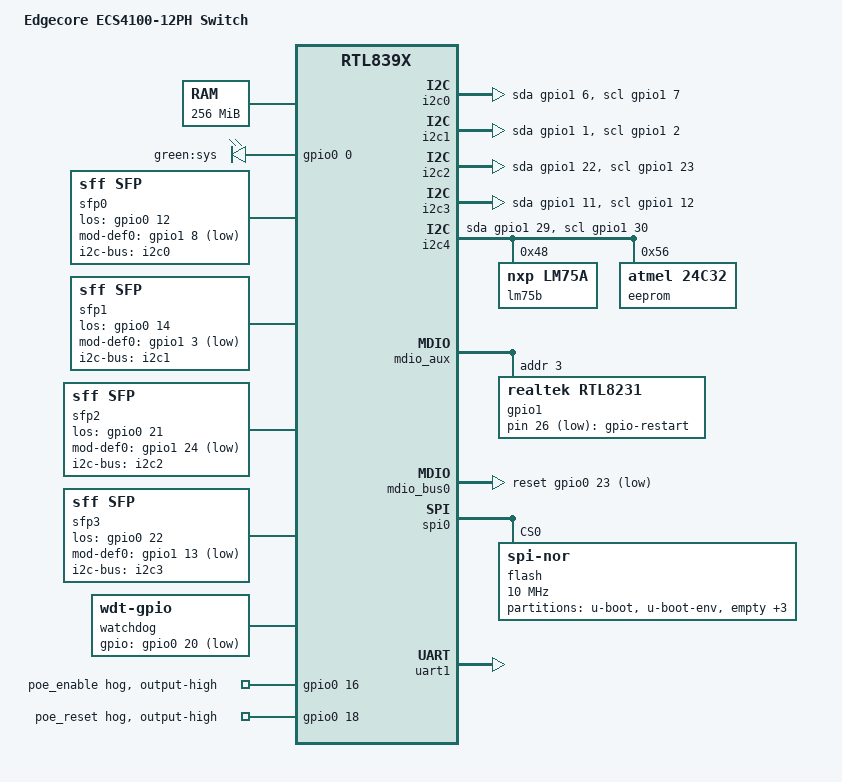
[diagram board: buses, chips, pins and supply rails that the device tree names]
// SPDX-License-Identifier: GPL-2.0-or-later

#include "rtl839x.dtsi"

#include <dt-bindings/input/input.h>
#include <dt-bindings/gpio/gpio.h>

/ {
	compatible = "edgecore,ecs4100-12ph", "realtek,rtl839x-soc";
	model = "Edgecore ECS4100-12PH Switch";

	aliases {
		label-mac-device = &ethernet0;
		led-boot = &led_sys;
		led-failsafe = &led_sys;
		led-running = &led_sys;
		led-upgrade = &led_sys;
	};

	memory@0 {
		device_type = "memory";
		reg = <0x0 0x10000000>;
	};

	leds {
		pinctrl-names = "default";
		pinctrl-0 = <&pinmux_disable_sys_led>;
		compatible = "gpio-leds";

		led_sys: sys {
			label = "green:sys";
			gpios = <&gpio0 0 GPIO_ACTIVE_HIGH>;
		};
	};

	gpio-restart {
		compatible = "gpio-restart";
		gpios = <&gpio1 26 GPIO_ACTIVE_LOW>;
	};

	i2c0: i2c-gpio-0 {
		compatible = "i2c-gpio";
		sda-gpios = <&gpio1 6 (GPIO_ACTIVE_HIGH | GPIO_OPEN_DRAIN)>;
		scl-gpios = <&gpio1 7 (GPIO_ACTIVE_HIGH | GPIO_OPEN_DRAIN)>;
		i2c-gpio,delay-us = <2>;
		#address-cells = <1>;
		#size-cells = <0>;
	};

	sfp0: sfp-p9 {
		compatible = "sff,sfp";
		i2c-bus = <&i2c0>;
		los-gpio = <&gpio0 12 GPIO_ACTIVE_HIGH>;
		mod-def0-gpio = <&gpio1 8 GPIO_ACTIVE_LOW>;
	};

	i2c1: i2c-gpio-1 {
		compatible = "i2c-gpio";
		sda-gpios = <&gpio1 1 (GPIO_ACTIVE_HIGH | GPIO_OPEN_DRAIN)>;
		scl-gpios = <&gpio1 2 (GPIO_ACTIVE_HIGH | GPIO_OPEN_DRAIN)>;
		i2c-gpio,delay-us = <2>;
		#address-cells = <1>;
		#size-cells = <0>;
	};

	sfp1: sfp-p10 {
		compatible = "sff,sfp";
		i2c-bus = <&i2c1>;
		los-gpio = <&gpio0 14 GPIO_ACTIVE_HIGH>;
		mod-def0-gpio = <&gpio1 3 GPIO_ACTIVE_LOW>;
	};

	i2c2: i2c-gpio-2 {
		compatible = "i2c-gpio";
		sda-gpios = <&gpio1 22 (GPIO_ACTIVE_HIGH | GPIO_OPEN_DRAIN)>;
		scl-gpios = <&gpio1 23 (GPIO_ACTIVE_HIGH | GPIO_OPEN_DRAIN)>;
		i2c-gpio,delay-us = <2>;
		#address-cells = <1>;
		#size-cells = <0>;
	};

	sfp2: sfp-p11 {
		compatible = "sff,sfp";
		i2c-bus = <&i2c2>;
		los-gpio = <&gpio0 21 GPIO_ACTIVE_HIGH>;
		mod-def0-gpio = <&gpio1 24 GPIO_ACTIVE_LOW>;
	};

	i2c3: i2c-gpio-3 {
		compatible = "i2c-gpio";
		sda-gpios = <&gpio1 11 (GPIO_ACTIVE_HIGH | GPIO_OPEN_DRAIN)>;
		scl-gpios = <&gpio1 12 (GPIO_ACTIVE_HIGH | GPIO_OPEN_DRAIN)>;
		i2c-gpio,delay-us = <2>;
		#address-cells = <1>;
		#size-cells = <0>;
	};

	sfp3: sfp-p12 {
		compatible = "sff,sfp";
		i2c-bus = <&i2c3>;
		los-gpio = <&gpio0 22 GPIO_ACTIVE_HIGH>;
		mod-def0-gpio = <&gpio1 13 GPIO_ACTIVE_LOW>;
	};

	i2c4: i2c-gpio-4 {
		compatible = "i2c-gpio";
		sda-gpios = <&gpio1 29 (GPIO_ACTIVE_HIGH | GPIO_OPEN_DRAIN)>;
		scl-gpios = <&gpio1 30 (GPIO_ACTIVE_HIGH | GPIO_OPEN_DRAIN)>;
		i2c-gpio,delay-us = <2>;
		#address-cells = <1>;
		#size-cells = <0>;

		lm75b@48 {
			compatible = "nxp,lm75a";
			reg = <0x48>;
		};

		eeprom@56 {
			compatible = "atmel,24c32";
			reg = <0x56>;
		};
	};

	watchdog {
		compatible = "linux,wdt-gpio";
		gpios = <&gpio0 20 GPIO_ACTIVE_LOW>;
		hw_algo = "toggle";
		hw_margin_ms = <1200>;
	};
};

&ethernet0 {
	nvmem-cells = <&macaddr_factory>;
	nvmem-cell-names = "mac-address";
};

&gpio0 {
	poe_enable {
		gpio-hog;
		gpios = <16 GPIO_ACTIVE_HIGH>;
		output-high;
	};

	poe_reset {
		gpio-hog;
		gpios = <18 GPIO_ACTIVE_HIGH>;
		output-high;
	};
};

&mdio_aux {
	status = "okay";

	gpio1: expander@3 {
		compatible = "realtek,rtl8231";
		reg = <3>;

		gpio-controller;
		#gpio-cells = <2>;
		gpio-ranges = <&gpio1 0 0 37>;

		led-controller {
			compatible = "realtek,rtl8231-leds";
			status = "disabled";
		};
	};
};

&mdio_bus0 {
	reset-gpios = <&gpio0 23 GPIO_ACTIVE_LOW>;
	reset-delay-us = <2000>;
	reset-post-delay-us = <140000>;

	/* External phy RTL8218B */
	PHY_C22(0, 0)
	PHY_C22(1, 1)
	PHY_C22(2, 2)
	PHY_C22(3, 3)
	PHY_C22(4, 4)
	PHY_C22(5, 5)
	PHY_C22(6, 6)
	PHY_C22(7, 7)
};

&mdio_bus1 {
	/* External phy RTL8214FC */
	PHY_C22_SFP(48, 24, 0)
	PHY_C22_SFP(49, 25, 1)
	PHY_C22_SFP(50, 26, 2)
	PHY_C22_SFP(51, 27, 3)
};

&spi0 {
	status = "okay";

	flash@0 {
		compatible = "jedec,spi-nor";
		reg = <0>;
		spi-max-frequency = <10000000>;

		partitions {
			compatible = "fixed-partitions";
			#address-cells = <1>;
			#size-cells = <1>;

			partition@0 {
				label = "u-boot";
				reg = <0x0 0x40000>;
				read-only;
			};
			partition@100000 {
				label = "u-boot-env";
				reg = <0x100000 0x20000>;
			};
			partition@120000 {
				label = "empty";
				reg = <0x120000 0x60000>;
				read-only;
			};
			partition@180000 {
				label = "para";
				reg = <0x180000 0x20000>;
				read-only;

				nvmem-layout {
					compatible = "fixed-layout";
					#address-cells = <1>;
					#size-cells = <1>;

					macaddr_factory: macaddr@0 {
						reg = <0x0 0x6>;
					};
				};
			};
			partition@200000 {
				label = "firmware";
				reg = <0x200000 0xdf0000>;
				compatible = "openwrt,uimage", "denx,uimage";
			};
			partition@ff0000 {
				label = "certificates";
				reg = <0xff0000 0x10000>;
			};
		};
	};
};

&switch0 {
	ethernet-ports {
		#address-cells = <1>;
		#size-cells = <0>;

		SWITCH_PORT_SDS(0, 1, 0, 0, qsgmii)
		SWITCH_PORT_SDS(1, 2, 0, 1, qsgmii)
		SWITCH_PORT_SDS(2, 3, 0, 2, qsgmii)
		SWITCH_PORT_SDS(3, 4, 0, 3, qsgmii)
		SWITCH_PORT_SDS(4, 5, 1, 0, qsgmii)
		SWITCH_PORT_SDS(5, 6, 1, 1, qsgmii)
		SWITCH_PORT_SDS(6, 7, 1, 2, qsgmii)
		SWITCH_PORT_SDS(7, 8, 1, 3, qsgmii)

		SWITCH_PORT_SDS(48, 9, 12, 0, qsgmii)
		SWITCH_PORT_SDS(49, 10, 12, 1, qsgmii)
		SWITCH_PORT_SDS(50, 11, 12, 2, qsgmii)
		SWITCH_PORT_SDS(51, 12, 12, 3, qsgmii)

		port@52 {
			ethernet = <&ethernet0>;
			reg = <52>;
			phy-mode = "internal";

			fixed-link {
				speed = <1000>;
				full-duplex;
			};
		};
	};
};

&uart1 {
	status = "okay";
};
